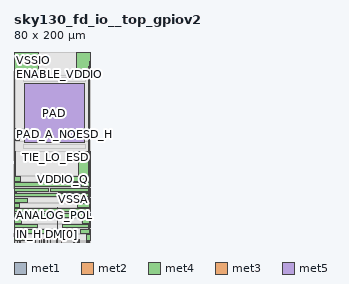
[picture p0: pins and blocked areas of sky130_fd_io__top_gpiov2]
MACRO sky130_fd_io__top_gpiov2
  CLASS PAD ;
  FOREIGN sky130_fd_io__top_gpiov2 ;
  ORIGIN 0.000 0.000 ;
  SIZE 80.000 BY 200.000 ;
  SYMMETRY X Y R90 ;
  PIN ANALOG_EN
    DIRECTION INPUT ;
    USE SIGNAL ;
    ANTENNAGATEAREA 0.640000 ;
    PORT
      LAYER met1 ;
        RECT 62.430 0.000 62.690 1.305 ;
    END
  END ANALOG_EN
  PIN DM[0]
    DIRECTION INPUT ;
    USE SIGNAL ;
    ANTENNAGATEAREA 0.500000 ;
    PORT
      LAYER met2 ;
        RECT 49.855 0.000 50.115 0.545 ;
    END
  END DM[0]
  PIN DM[1]
    DIRECTION INPUT ;
    USE SIGNAL ;
    ANTENNAGATEAREA 0.500000 ;
    PORT
      LAYER met2 ;
        RECT 66.835 0.000 67.095 1.195 ;
    END
  END DM[1]
  PIN DM[2]
    DIRECTION INPUT ;
    USE SIGNAL ;
    ANTENNAGATEAREA 0.500000 ;
    PORT
      LAYER met2 ;
        RECT 28.490 0.000 28.750 4.070 ;
    END
  END DM[2]
  PIN HLD_H_N
    DIRECTION INPUT ;
    USE SIGNAL ;
    ANTENNAGATEAREA 1.620000 ;
    PORT
      LAYER met2 ;
        RECT 31.815 0.000 32.075 3.340 ;
    END
  END HLD_H_N
  PIN HLD_OVR
    DIRECTION INPUT ;
    USE SIGNAL ;
    ANTENNAGATEAREA 0.500000 ;
    PORT
      LAYER met2 ;
        RECT 26.600 0.000 26.860 2.705 ;
    END
  END HLD_OVR
  PIN INP_DIS
    DIRECTION INPUT ;
    USE SIGNAL ;
    ANTENNAGATEAREA 0.500000 ;
    PORT
      LAYER met2 ;
        RECT 45.245 0.000 45.505 5.090 ;
    END
  END INP_DIS
  PIN ENABLE_VDDA_H
    DIRECTION INPUT ;
    USE SIGNAL ;
    ANTENNAGATEAREA 3.500000 ;
    PORT
      LAYER met2 ;
        RECT 12.755 0.000 13.015 5.350 ;
    END
  END ENABLE_VDDA_H
  PIN VTRIP_SEL
    DIRECTION INPUT ;
    USE SIGNAL ;
    ANTENNAGATEAREA 0.500000 ;
    PORT
      LAYER met2 ;
        RECT 6.130 0.000 6.390 1.550 ;
    END
  END VTRIP_SEL
  PIN OE_N
    DIRECTION INPUT ;
    USE SIGNAL ;
    ANTENNAGATEAREA 1.250000 ;
    PORT
      LAYER met2 ;
        RECT 3.375 0.000 3.605 4.475 ;
    END
  END OE_N
  PIN OUT
    DIRECTION INPUT ;
    USE SIGNAL ;
    ANTENNAGATEAREA 1.529000 ;
    PORT
      LAYER met2 ;
        RECT 22.355 0.000 22.615 6.425 ;
    END
  END OUT
  PIN SLOW
    DIRECTION INPUT ;
    USE SIGNAL ;
    ANTENNAGATEAREA 0.500000 ;
    PORT
      LAYER met2 ;
        RECT 77.610 0.000 77.870 1.185 ;
    END
  END SLOW
  PIN TIE_LO_ESD
    DIRECTION OUTPUT ;
    USE SIGNAL ;
    PORT
      LAYER met2 ;
        RECT 79.715 0.000 79.915 177.870 ;
    END
  END TIE_LO_ESD
  PIN PAD_A_ESD_0_H
    DIRECTION INOUT ;
    USE SIGNAL ;
    PORT
      LAYER met2 ;
        RECT 76.280 0.000 76.920 2.055 ;
    END
  END PAD_A_ESD_0_H
  PIN ANALOG_SEL
    DIRECTION INPUT ;
    USE SIGNAL ;
    ANTENNAGATEAREA 0.279000 ;
    PORT
      LAYER met2 ;
        RECT 30.750 0.000 31.010 2.265 ;
    END
  END ANALOG_SEL
  PIN ENABLE_INP_H
    DIRECTION INPUT ;
    USE SIGNAL ;
    ANTENNAGATEAREA 3.240000 ;
    PORT
      LAYER met2 ;
        RECT 38.390 0.000 38.650 3.090 ;
    END
  END ENABLE_INP_H
  PIN PAD_A_ESD_1_H
    DIRECTION INOUT ;
    USE SIGNAL ;
    PORT
      LAYER met2 ;
        RECT 68.275 0.000 68.925 2.270 ;
    END
  END PAD_A_ESD_1_H
  PIN TIE_HI_ESD
    DIRECTION OUTPUT ;
    USE SIGNAL ;
    PORT
      LAYER met2 ;
        RECT 78.705 0.000 78.905 1.215 ;
    END
  END TIE_HI_ESD
  PIN ENABLE_H
    DIRECTION INPUT ;
    USE SIGNAL ;
    ANTENNAGATEAREA 4.860000 ;
    PORT
      LAYER met2 ;
        RECT 35.460 0.000 35.720 1.550 ;
    END
  END ENABLE_H
  PIN IB_MODE_SEL
    DIRECTION INPUT ;
    USE SIGNAL ;
    ANTENNAGATEAREA 0.500000 ;
    PORT
      LAYER met2 ;
        RECT 5.420 0.000 5.650 4.475 ;
    END
  END IB_MODE_SEL
  PIN ENABLE_VSWITCH_H
    DIRECTION INPUT ;
    USE SIGNAL ;
    ANTENNAGATEAREA 3.120000 ;
    PORT
      LAYER met2 ;
        RECT 16.310 0.000 16.570 2.320 ;
    END
  END ENABLE_VSWITCH_H
  PIN VSSD
    DIRECTION INOUT ;
    USE GROUND ;
    PORT
      LAYER met4 ;
        RECT 0.000 41.585 13.910 46.235 ;
    END
    PORT
      LAYER met4 ;
        RECT 55.705 41.585 80.000 46.235 ;
    END
  END VSSD
  PIN AMUXBUS_B
    DIRECTION INOUT ;
    USE SIGNAL ;
    ANTENNADIFFAREA 23.275000 ;
    PORT
      LAYER met4 ;
        RECT 0.000 48.365 52.145 51.345 ;
    END
    PORT
      LAYER met4 ;
        RECT 54.465 48.365 80.000 51.345 ;
    END
  END AMUXBUS_B
  PIN AMUXBUS_A
    DIRECTION INOUT ;
    USE SIGNAL ;
    ANTENNADIFFAREA 23.275000 ;
    PORT
      LAYER met4 ;
        RECT 0.000 53.125 36.440 56.105 ;
    END
    PORT
      LAYER met4 ;
        RECT 38.760 53.125 80.000 56.105 ;
    END
  END AMUXBUS_A
  PIN VDDIO_Q
    DIRECTION INOUT ;
    USE POWER ;
    PORT
      LAYER met4 ;
        RECT 0.000 64.085 6.860 68.535 ;
    END
    PORT
      LAYER met4 ;
        RECT 60.945 64.085 80.000 68.535 ;
    END
  END VDDIO_Q
  PIN VDDIO
    DIRECTION INOUT ;
    USE POWER ;
    PORT
      LAYER met4 ;
        RECT 0.000 70.035 1.460 95.000 ;
    END
    PORT
      LAYER met4 ;
        RECT 0.000 19.785 7.430 24.435 ;
    END
    PORT
      LAYER met4 ;
        RECT 68.030 70.035 80.000 95.000 ;
    END
    PORT
      LAYER met4 ;
        RECT 71.735 19.785 80.000 24.435 ;
    END
  END VDDIO
  PIN VSWITCH
    DIRECTION INOUT ;
    USE POWER ;
    PORT
      LAYER met4 ;
        RECT 0.000 31.885 22.270 35.335 ;
    END
    PORT
      LAYER met4 ;
        RECT 23.850 31.885 80.000 35.335 ;
    END
  END VSWITCH
  PIN VSSIO
    DIRECTION INOUT ;
    USE GROUND ;
    PORT
      LAYER met4 ;
        RECT 0.000 25.835 19.330 30.485 ;
    END
    PORT
      LAYER met4 ;
        RECT 21.530 25.835 80.000 30.485 ;
    END
    PORT
      LAYER met4 ;
        RECT 66.230 175.785 80.000 200.000 ;
    END
    PORT
      LAYER met4 ;
        RECT 0.000 175.785 25.550 200.000 ;
    END
  END VSSIO
  PIN VDDA
    DIRECTION INOUT ;
    USE POWER ;
    PORT
      LAYER met4 ;
        RECT 0.000 14.935 24.590 18.385 ;
    END
    PORT
      LAYER met4 ;
        RECT 51.570 14.935 80.000 18.385 ;
    END
  END VDDA
  PIN VCCD
    DIRECTION INOUT ;
    USE POWER ;
    PORT
      LAYER met4 ;
        RECT 0.000 8.885 34.235 13.535 ;
    END
    PORT
      LAYER met4 ;
        RECT 70.265 8.885 80.000 13.535 ;
    END
  END VCCD
  PIN VCCHIB
    DIRECTION INOUT ;
    USE POWER ;
    PORT
      LAYER met4 ;
        RECT 0.000 2.035 11.150 7.485 ;
    END
    PORT
      LAYER met4 ;
        RECT 76.810 2.035 80.000 7.485 ;
    END
  END VCCHIB
  PIN VSSA
    DIRECTION INOUT ;
    USE GROUND ;
    PORT
      LAYER met4 ;
        RECT 0.000 56.405 2.610 56.735 ;
    END
    PORT
      LAYER met4 ;
        RECT 0.000 47.735 2.610 48.065 ;
    END
    PORT
      LAYER met4 ;
        RECT 0.000 51.645 2.610 52.825 ;
    END
    PORT
      LAYER met4 ;
        RECT 0.000 36.735 5.435 40.185 ;
    END
    PORT
      LAYER met4 ;
        RECT 67.310 36.735 80.000 40.185 ;
    END
    PORT
      LAYER met4 ;
        RECT 47.090 56.405 80.000 56.735 ;
    END
    PORT
      LAYER met4 ;
        RECT 47.090 47.735 80.000 48.065 ;
    END
    PORT
      LAYER met4 ;
        RECT 47.090 51.645 80.000 52.825 ;
    END
  END VSSA
  PIN VSSIO_Q
    DIRECTION INOUT ;
    USE GROUND ;
    PORT
      LAYER met4 ;
        RECT 0.000 58.235 69.845 62.685 ;
    END
    PORT
      LAYER met4 ;
        RECT 71.575 58.235 80.000 62.685 ;
    END
  END VSSIO_Q
  PIN PAD_A_NOESD_H
    DIRECTION INOUT ;
    USE SIGNAL ;
    PORT
      LAYER met4 ;
        RECT 2.000 106.585 5.470 118.955 ;
    END
    PORT
      LAYER met3 ;
        RECT 62.820 0.000 63.890 9.705 ;
    END
  END PAD_A_NOESD_H
  PIN PAD
    DIRECTION INOUT ;
    USE SIGNAL ;
    ANTENNADIFFAREA 426.799988 ;
    PORT
      LAYER met5 ;
        RECT 11.200 104.560 73.800 167.010 ;
    END
  END PAD
  PIN ANALOG_POL
    DIRECTION INPUT ;
    USE SIGNAL ;
    ANTENNAGATEAREA 0.279000 ;
    PORT
      LAYER met3 ;
        RECT 45.865 0.000 46.195 36.805 ;
    END
  END ANALOG_POL
  PIN ENABLE_VDDIO
    DIRECTION INPUT ;
    USE SIGNAL ;
    ANTENNAGATEAREA 3.240000 ;
    PORT
      LAYER met3 ;
        RECT 78.580 0.000 78.910 184.775 ;
    END
  END ENABLE_VDDIO
  PIN IN
    DIRECTION OUTPUT ;
    USE SIGNAL ;
    ANTENNADIFFAREA 2.520000 ;
    PORT
      LAYER met3 ;
        RECT 79.240 0.000 79.570 189.560 ;
    END
  END IN
  PIN IN_H
    DIRECTION OUTPUT ;
    USE SIGNAL ;
    ANTENNADIFFAREA 6.850000 ;
    PORT
      LAYER met3 ;
        RECT 0.400 0.000 1.020 178.485 ;
    END
  END IN_H
  OBS
      LAYER nwell ;
        RECT 0.000 178.975 80.000 200.000 ;
        RECT -0.415 170.230 80.435 178.975 ;
        RECT -0.415 144.880 80.440 170.230 ;
        RECT 0.000 144.565 80.000 144.880 ;
      LAYER pwell ;
        RECT -0.290 140.685 80.290 144.565 ;
      LAYER nwell ;
        RECT 0.000 140.385 80.000 140.685 ;
        RECT 0.000 140.380 80.440 140.385 ;
        RECT -0.415 130.665 80.440 140.380 ;
        RECT 0.000 130.355 80.000 130.665 ;
      LAYER pwell ;
        RECT -0.215 129.315 40.245 130.355 ;
      LAYER nwell ;
        RECT 40.245 129.315 66.910 130.355 ;
      LAYER pwell ;
        RECT 66.910 129.315 80.290 130.355 ;
        RECT -0.215 125.135 80.290 129.315 ;
        RECT -0.215 103.550 5.735 125.135 ;
      LAYER nwell ;
        RECT 5.735 103.550 77.865 125.135 ;
      LAYER pwell ;
        RECT 77.865 103.550 80.290 125.135 ;
        RECT -0.215 101.965 80.290 103.550 ;
        RECT -0.215 96.255 5.215 101.965 ;
      LAYER nwell ;
        RECT 5.215 100.820 39.385 101.965 ;
      LAYER pwell ;
        RECT 39.385 100.820 80.290 101.965 ;
      LAYER nwell ;
        RECT 5.215 99.520 52.880 100.820 ;
      LAYER pwell ;
        RECT 52.880 99.520 80.290 100.820 ;
      LAYER nwell ;
        RECT 5.215 97.985 76.770 99.520 ;
      LAYER pwell ;
        RECT 76.770 97.985 80.290 99.520 ;
      LAYER nwell ;
        RECT 5.215 96.255 39.385 97.985 ;
      LAYER pwell ;
        RECT 39.385 96.255 80.290 97.985 ;
        RECT -0.215 95.975 80.290 96.255 ;
        RECT -0.215 95.260 45.840 95.975 ;
      LAYER nwell ;
        RECT 45.840 95.260 80.000 95.975 ;
      LAYER pwell ;
        RECT -0.215 94.955 46.590 95.260 ;
      LAYER nwell ;
        RECT 46.590 95.165 80.000 95.260 ;
        RECT 46.590 94.955 80.670 95.165 ;
      LAYER pwell ;
        RECT -0.215 92.935 9.300 94.955 ;
      LAYER nwell ;
        RECT 9.300 92.935 80.670 94.955 ;
        RECT 0.000 92.400 80.670 92.935 ;
        RECT -0.415 88.485 80.670 92.400 ;
        RECT -0.120 85.580 80.670 88.485 ;
        RECT 0.000 81.235 80.670 85.580 ;
        RECT -0.715 56.590 80.670 81.235 ;
        RECT 0.000 50.620 80.670 56.590 ;
        RECT 0.000 36.055 80.000 50.620 ;
        RECT 0.000 29.785 80.450 36.055 ;
        RECT 0.000 25.345 80.000 29.785 ;
        RECT 0.000 19.155 80.450 25.345 ;
        RECT 0.000 9.325 80.000 19.155 ;
        RECT -0.415 5.665 80.000 9.325 ;
        RECT 0.000 0.000 80.000 5.665 ;
      LAYER li1 ;
        RECT 0.000 178.645 80.000 199.705 ;
        RECT -0.085 170.090 80.105 178.645 ;
        RECT -0.115 145.215 80.105 170.090 ;
        RECT -0.115 145.155 80.000 145.215 ;
        RECT 0.000 144.435 80.000 145.155 ;
        RECT -0.160 140.815 80.160 144.435 ;
        RECT 0.000 140.150 80.000 140.815 ;
        RECT -0.115 140.055 80.000 140.150 ;
        RECT -0.115 131.275 80.085 140.055 ;
        RECT -0.085 130.995 80.085 131.275 ;
        RECT 0.000 130.225 80.000 130.995 ;
        RECT -0.085 130.220 80.160 130.225 ;
        RECT -0.115 96.105 80.160 130.220 ;
        RECT -0.115 95.895 80.000 96.105 ;
        RECT -0.085 94.580 80.000 95.895 ;
        RECT -0.085 93.065 80.085 94.580 ;
        RECT 0.000 92.070 80.085 93.065 ;
        RECT -0.085 88.815 80.085 92.070 ;
        RECT 0.000 80.605 80.085 88.815 ;
        RECT -0.085 57.220 80.085 80.605 ;
        RECT 0.000 51.250 80.085 57.220 ;
        RECT 0.000 35.725 80.000 51.250 ;
        RECT 0.000 30.115 80.120 35.725 ;
        RECT 0.000 25.015 80.000 30.115 ;
        RECT 0.000 19.485 80.120 25.015 ;
        RECT 0.000 8.995 80.000 19.485 ;
        RECT -0.085 5.995 80.000 8.995 ;
        RECT 0.000 0.230 80.000 5.995 ;
      LAYER met1 ;
        RECT 0.000 180.975 80.000 200.000 ;
        RECT 0.000 178.900 80.020 180.975 ;
        RECT 0.000 170.090 80.000 178.900 ;
        RECT -0.115 131.275 80.145 170.090 ;
        RECT 0.000 130.220 80.000 131.275 ;
        RECT -0.115 95.895 80.145 130.220 ;
        RECT 0.000 94.580 80.000 95.895 ;
        RECT 0.000 91.480 80.060 94.580 ;
        RECT -0.145 89.750 80.060 91.480 ;
        RECT 0.000 80.635 80.060 89.750 ;
        RECT -0.115 72.930 80.060 80.635 ;
        POLYGON 80.060 72.985 80.115 72.930 80.060 72.930 ;
        RECT -0.115 57.190 80.115 72.930 ;
        RECT 0.000 51.220 80.115 57.190 ;
        RECT 0.000 35.725 80.000 51.220 ;
        RECT 0.000 30.120 80.115 35.725 ;
        RECT 0.000 25.015 80.000 30.120 ;
        RECT 0.000 19.485 80.115 25.015 ;
        RECT 0.000 1.585 80.000 19.485 ;
        RECT 0.000 0.260 62.150 1.585 ;
        RECT 62.970 0.260 80.000 1.585 ;
      LAYER met2 ;
        RECT 0.210 178.150 79.915 200.000 ;
        RECT 0.210 6.705 79.435 178.150 ;
        RECT 0.210 5.630 22.075 6.705 ;
        RECT 0.210 4.755 12.475 5.630 ;
        RECT 0.210 0.250 3.095 4.755 ;
        RECT 3.885 0.250 5.140 4.755 ;
        RECT 5.930 1.830 12.475 4.755 ;
        RECT 6.670 0.250 12.475 1.830 ;
        RECT 13.295 2.600 22.075 5.630 ;
        RECT 13.295 0.250 16.030 2.600 ;
        RECT 16.850 0.250 22.075 2.600 ;
        RECT 22.895 5.370 79.435 6.705 ;
        RECT 22.895 4.350 44.965 5.370 ;
        RECT 22.895 2.985 28.210 4.350 ;
        RECT 22.895 0.250 26.320 2.985 ;
        RECT 27.140 0.250 28.210 2.985 ;
        RECT 29.030 3.620 44.965 4.350 ;
        RECT 29.030 2.545 31.535 3.620 ;
        RECT 29.030 0.250 30.470 2.545 ;
        RECT 31.290 0.250 31.535 2.545 ;
        RECT 32.355 3.370 44.965 3.620 ;
        RECT 32.355 1.830 38.110 3.370 ;
        RECT 32.355 0.250 35.180 1.830 ;
        RECT 36.000 0.250 38.110 1.830 ;
        RECT 38.930 0.250 44.965 3.370 ;
        RECT 45.785 2.550 79.435 5.370 ;
        RECT 45.785 1.475 67.995 2.550 ;
        RECT 45.785 0.825 66.555 1.475 ;
        RECT 45.785 0.250 49.575 0.825 ;
        RECT 50.395 0.250 66.555 0.825 ;
        RECT 67.375 0.250 67.995 1.475 ;
        RECT 69.205 2.335 79.435 2.550 ;
        RECT 69.205 0.250 76.000 2.335 ;
        RECT 77.200 1.495 79.435 2.335 ;
        RECT 77.200 1.465 78.425 1.495 ;
        RECT 77.200 0.250 77.330 1.465 ;
        RECT 78.150 0.250 78.425 1.465 ;
        RECT 79.185 0.250 79.435 1.495 ;
      LAYER met3 ;
        RECT 0.400 189.960 79.570 200.000 ;
        RECT 0.400 185.175 78.840 189.960 ;
        RECT 0.400 178.885 78.180 185.175 ;
        RECT 1.420 37.205 78.180 178.885 ;
        RECT 1.420 0.245 45.465 37.205 ;
        RECT 46.595 10.105 78.180 37.205 ;
        RECT 46.595 0.245 62.420 10.105 ;
        RECT 64.290 0.245 78.180 10.105 ;
      LAYER met4 ;
        RECT 25.950 175.385 65.830 200.000 ;
        RECT 1.345 119.355 78.165 175.385 ;
        RECT 1.345 106.185 1.600 119.355 ;
        RECT 5.870 106.185 78.165 119.355 ;
        RECT 1.345 95.400 78.165 106.185 ;
        RECT 1.860 69.635 67.630 95.400 ;
        RECT 1.345 68.935 78.165 69.635 ;
        RECT 7.260 63.685 60.545 68.935 ;
        RECT 1.345 63.085 78.165 63.685 ;
        RECT 70.245 57.835 71.175 63.085 ;
        RECT 1.345 57.135 78.165 57.835 ;
        RECT 3.010 56.505 46.690 57.135 ;
        RECT 36.840 52.725 38.360 56.505 ;
        RECT 3.010 51.745 46.690 52.725 ;
        RECT 52.545 48.465 54.065 51.245 ;
        RECT 3.010 47.335 46.690 47.965 ;
        RECT 1.345 46.635 78.165 47.335 ;
        RECT 14.310 41.185 55.305 46.635 ;
        RECT 1.345 40.585 78.165 41.185 ;
        RECT 5.835 36.335 66.910 40.585 ;
        RECT 1.345 35.735 78.165 36.335 ;
        RECT 22.670 31.485 23.450 35.735 ;
        RECT 1.345 30.885 78.165 31.485 ;
        RECT 19.730 25.435 21.130 30.885 ;
        RECT 1.345 24.835 78.165 25.435 ;
        RECT 7.830 19.385 71.335 24.835 ;
        RECT 1.345 18.785 78.165 19.385 ;
        RECT 24.990 14.535 51.170 18.785 ;
        RECT 1.345 13.935 78.165 14.535 ;
        RECT 34.635 8.485 69.865 13.935 ;
        RECT 1.345 7.885 78.165 8.485 ;
        RECT 11.550 1.635 76.410 7.885 ;
        RECT 1.345 0.535 78.165 1.635 ;
      LAYER met5 ;
        RECT 9.800 168.610 75.200 173.485 ;
        RECT 9.800 98.085 75.200 102.960 ;
  END
END sky130_fd_io__top_gpiov2
END LIBRARY
